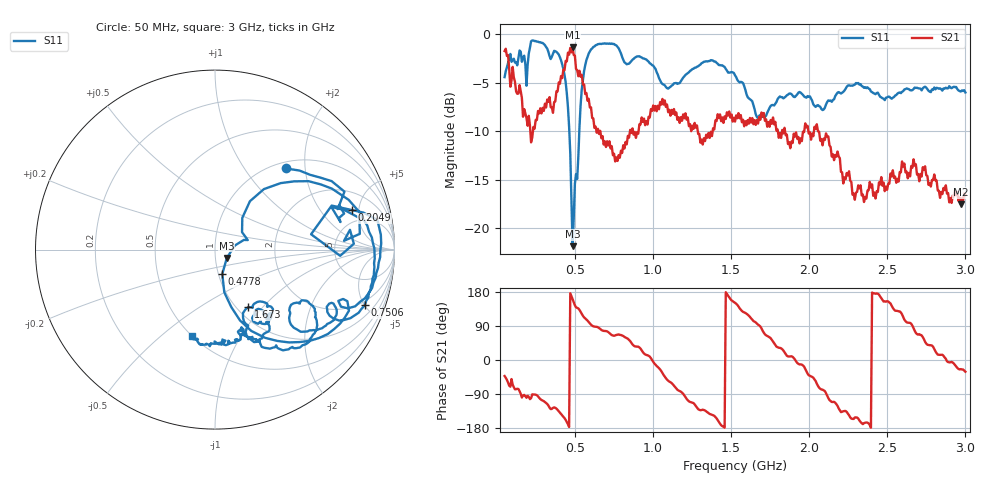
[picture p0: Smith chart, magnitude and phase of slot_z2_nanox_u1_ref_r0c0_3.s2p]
! nanovna_capture.py 2026-10-26T21:29:03+0900
! NanoVNA-F_V2 fw 0.6.0 SN 4A3639384505514B
! cal: load open short thru cal'ed  over 50000000-3000000000 Hz, 201 points
! points 401, avg 4
! slot line z=1.6, genuine Nano X, 0 deg, centred, placement 3
# HZ S RI R 50
! S12 and S22 are not measured (written as 0)
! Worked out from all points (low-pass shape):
!   401 points, 50 MHz to 3 GHz, reference 50 ohm
!   highest |S21| = -1.37 dB at 485.1 MHz (marker M1); lowest = -17.5 dB at 2.97 GHz (marker M2)
!   |S21| within 3 dB of the highest: start of sweep to 82.59 MHz; 420.1 MHz to 536.5 MHz (116.3 MHz wide, 24.3 % of centre) (the widest 2 of 5)
!   lowest |S11| = -21.9 dB at 485.1 MHz (marker M3), VSWR 1.18, Z = 56.8 - j5.37 ohm
!   |S11| at or under -10 dB: 464.2 MHz to 528.3 MHz (64.12 MHz wide, 12.9 % of centre)
!   S12 and S22 are empty: the file has one direction only
!   S11 on the Smith chart (normalised r, x): 50 MHz: 1.12, +1.59; 204.9 MHz: 3.53, +4.23; 477.8 MHz: 1.04, -0.29; 750.6 MHz: 1.68, -5.01; 1.673 GHz: 1.12, -0.83; 3 GHz: 0.50, -0.64
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5e7  0.395 0.4522  0.6053 -0.5505  0 0  0 0
1.68e8  0.752 0.1101  -0.0231 -0.3746  0 0  0 0
2.04875e8  0.7641 0.2201  -0.0487 -0.3762  0 0  0 0
2.78625e8  0.8945 -0.1578  -0.0941 -0.4041  0 0  0 0
4.11375e8  0.5283 -0.5083  -0.4849 -0.3675  0 0  0 0
4.4825e8  0.2021 -0.4531  -0.6945 -0.2039  0 0  0 0
4.7775e8  0.0406 -0.1358  -0.7904 0.1571  0 0  0 0
4.85125e8  0.0657 -0.047  -0.8061 0.2818  0 0  0 0
5.44125e8  0.366 0.3705  -0.3196 0.5278  0 0  0 0
6.17875e8  0.8483 0.1344  0.00798 0.3673  0 0  0 0
7.50625e8  0.8342 -0.3105  0.1067 0.2171  0 0  0 0
1.03825e9  0.4228 -0.4175  0.3816 -0.1505  0 0  0 0
1.207875e9  0.5348 -0.3063  -0.0531 -0.3871  0 0  0 0
1.525e9  0.277 -0.5474  -0.3103 0.1713  0 0  0 0
1.6725e9  0.184 -0.3204  -0.0194 0.3456  0 0  0 0
1.783125e9  0.3039 -0.315  0.272 0.2254  0 0  0 0
2.019125e9  0.2138 -0.4  0.2187 -0.216  0 0  0 0
2.196125e9  0.2876 -0.4072  -0.1551 -0.1693  0 0  0 0
2.51325e9  0.1463 -0.4526  -0.1493 0.081  0 0  0 0
2.668125e9  0.1144 -0.5087  0.0254 0.2249  0 0  0 0
2.9705e9  -0.0999 -0.4962  0.1213 -0.054  0 0  0 0
3e9  -0.1283 -0.4839  0.1274 -0.0764  0 0  0 0
